VERSION 5.7 ;
  NOWIREEXTENSIONATPIN ON ;
  DIVIDERCHAR "/" ;
  BUSBITCHARS "[]" ;
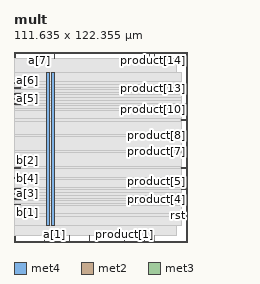
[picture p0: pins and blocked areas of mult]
MACRO mult
  CLASS BLOCK ;
  FOREIGN mult ;
  ORIGIN 0.000 0.000 ;
  SIZE 111.635 BY 122.355 ;
  PIN VGND
    DIRECTION INOUT ;
    USE GROUND ;
    PORT
      LAYER met4 ;
        RECT 24.340 10.640 25.940 109.040 ;
    END
  END VGND
  PIN VPWR
    DIRECTION INOUT ;
    USE POWER ;
    PORT
      LAYER met4 ;
        RECT 21.040 10.640 22.640 109.040 ;
    END
  END VPWR
  PIN a[0]
    DIRECTION INPUT ;
    USE SIGNAL ;
    ANTENNAGATEAREA 0.196500 ;
    PORT
      LAYER met2 ;
        RECT 35.510 0.000 35.790 4.000 ;
    END
  END a[0]
  PIN a[1]
    DIRECTION INPUT ;
    USE SIGNAL ;
    ANTENNAGATEAREA 0.196500 ;
    PORT
      LAYER met2 ;
        RECT 25.850 0.000 26.130 4.000 ;
    END
  END a[1]
  PIN a[2]
    DIRECTION INPUT ;
    USE SIGNAL ;
    ANTENNAGATEAREA 0.196500 ;
    PORT
      LAYER met3 ;
        RECT 0.000 27.240 4.000 27.840 ;
    END
  END a[2]
  PIN a[3]
    DIRECTION INPUT ;
    USE SIGNAL ;
    ANTENNAGATEAREA 0.196500 ;
    PORT
      LAYER met3 ;
        RECT 0.000 30.640 4.000 31.240 ;
    END
  END a[3]
  PIN a[4]
    DIRECTION INPUT ;
    USE SIGNAL ;
    ANTENNAGATEAREA 0.196500 ;
    PORT
      LAYER met3 ;
        RECT 0.000 88.440 4.000 89.040 ;
    END
  END a[4]
  PIN a[5]
    DIRECTION INPUT ;
    USE SIGNAL ;
    ANTENNAGATEAREA 0.196500 ;
    PORT
      LAYER met3 ;
        RECT 0.000 91.840 4.000 92.440 ;
    END
  END a[5]
  PIN a[6]
    DIRECTION INPUT ;
    USE SIGNAL ;
    ANTENNAGATEAREA 0.196500 ;
    PORT
      LAYER met3 ;
        RECT 0.000 98.640 4.000 99.240 ;
    END
  END a[6]
  PIN a[7]
    DIRECTION INPUT ;
    USE SIGNAL ;
    ANTENNAGATEAREA 0.196500 ;
    PORT
      LAYER met2 ;
        RECT 16.190 118.355 16.470 122.355 ;
    END
  END a[7]
  PIN b[0]
    DIRECTION INPUT ;
    USE SIGNAL ;
    ANTENNAGATEAREA 0.196500 ;
    PORT
      LAYER met2 ;
        RECT 19.410 0.000 19.690 4.000 ;
    END
  END b[0]
  PIN b[1]
    DIRECTION INPUT ;
    USE SIGNAL ;
    ANTENNAGATEAREA 0.196500 ;
    PORT
      LAYER met3 ;
        RECT 0.000 23.840 4.000 24.440 ;
    END
  END b[1]
  PIN b[2]
    DIRECTION INPUT ;
    USE SIGNAL ;
    ANTENNAGATEAREA 0.196500 ;
    PORT
      LAYER met3 ;
        RECT 0.000 47.640 4.000 48.240 ;
    END
  END b[2]
  PIN b[3]
    DIRECTION INPUT ;
    USE SIGNAL ;
    ANTENNAGATEAREA 0.196500 ;
    PORT
      LAYER met3 ;
        RECT 0.000 34.040 4.000 34.640 ;
    END
  END b[3]
  PIN b[4]
    DIRECTION INPUT ;
    USE SIGNAL ;
    ANTENNAGATEAREA 0.196500 ;
    PORT
      LAYER met3 ;
        RECT 0.000 40.840 4.000 41.440 ;
    END
  END b[4]
  PIN b[5]
    DIRECTION INPUT ;
    USE SIGNAL ;
    ANTENNAGATEAREA 0.196500 ;
    PORT
      LAYER met3 ;
        RECT 0.000 95.240 4.000 95.840 ;
    END
  END b[5]
  PIN b[6]
    DIRECTION INPUT ;
    USE SIGNAL ;
    ANTENNAGATEAREA 0.196500 ;
    PORT
      LAYER met2 ;
        RECT 22.630 118.355 22.910 122.355 ;
    END
  END b[6]
  PIN b[7]
    DIRECTION INPUT ;
    USE SIGNAL ;
    ANTENNAGATEAREA 0.196500 ;
    PORT
      LAYER met2 ;
        RECT 25.850 118.355 26.130 122.355 ;
    END
  END b[7]
  PIN clk
    DIRECTION INPUT ;
    USE SIGNAL ;
    ANTENNAGATEAREA 0.852000 ;
    PORT
      LAYER met3 ;
        RECT 0.000 102.040 4.000 102.640 ;
    END
  END clk
  PIN product[0]
    DIRECTION OUTPUT ;
    USE SIGNAL ;
    ANTENNADIFFAREA 0.445500 ;
    PORT
      LAYER met2 ;
        RECT 48.390 0.000 48.670 4.000 ;
    END
  END product[0]
  PIN product[10]
    DIRECTION OUTPUT ;
    USE SIGNAL ;
    ANTENNADIFFAREA 0.445500 ;
    PORT
      LAYER met3 ;
        RECT 107.635 85.040 111.635 85.640 ;
    END
  END product[10]
  PIN product[11]
    DIRECTION OUTPUT ;
    USE SIGNAL ;
    ANTENNADIFFAREA 0.445500 ;
    PORT
      LAYER met3 ;
        RECT 107.635 88.440 111.635 89.040 ;
    END
  END product[11]
  PIN product[12]
    DIRECTION OUTPUT ;
    USE SIGNAL ;
    ANTENNADIFFAREA 0.445500 ;
    PORT
      LAYER met3 ;
        RECT 107.635 95.240 111.635 95.840 ;
    END
  END product[12]
  PIN product[13]
    DIRECTION OUTPUT ;
    USE SIGNAL ;
    ANTENNADIFFAREA 0.445500 ;
    PORT
      LAYER met3 ;
        RECT 107.635 98.640 111.635 99.240 ;
    END
  END product[13]
  PIN product[14]
    DIRECTION OUTPUT ;
    USE SIGNAL ;
    ANTENNADIFFAREA 0.445500 ;
    PORT
      LAYER met2 ;
        RECT 90.250 118.355 90.530 122.355 ;
    END
  END product[14]
  PIN product[15]
    DIRECTION OUTPUT ;
    USE SIGNAL ;
    ANTENNADIFFAREA 0.445500 ;
    PORT
      LAYER met2 ;
        RECT 87.030 118.355 87.310 122.355 ;
    END
  END product[15]
  PIN product[1]
    DIRECTION OUTPUT ;
    USE SIGNAL ;
    ANTENNADIFFAREA 0.445500 ;
    PORT
      LAYER met2 ;
        RECT 70.930 0.000 71.210 4.000 ;
    END
  END product[1]
  PIN product[2]
    DIRECTION OUTPUT ;
    USE SIGNAL ;
    ANTENNADIFFAREA 0.445500 ;
    PORT
      LAYER met2 ;
        RECT 83.810 0.000 84.090 4.000 ;
    END
  END product[2]
  PIN product[3]
    DIRECTION OUTPUT ;
    USE SIGNAL ;
    ANTENNADIFFAREA 0.445500 ;
    PORT
      LAYER met2 ;
        RECT 90.250 0.000 90.530 4.000 ;
    END
  END product[3]
  PIN product[4]
    DIRECTION OUTPUT ;
    USE SIGNAL ;
    ANTENNADIFFAREA 0.445500 ;
    PORT
      LAYER met3 ;
        RECT 107.635 27.240 111.635 27.840 ;
    END
  END product[4]
  PIN product[5]
    DIRECTION OUTPUT ;
    USE SIGNAL ;
    ANTENNADIFFAREA 0.445500 ;
    PORT
      LAYER met3 ;
        RECT 107.635 34.040 111.635 34.640 ;
    END
  END product[5]
  PIN product[6]
    DIRECTION OUTPUT ;
    USE SIGNAL ;
    ANTENNADIFFAREA 0.445500 ;
    PORT
      LAYER met3 ;
        RECT 107.635 47.640 111.635 48.240 ;
    END
  END product[6]
  PIN product[7]
    DIRECTION OUTPUT ;
    USE SIGNAL ;
    ANTENNADIFFAREA 0.445500 ;
    PORT
      LAYER met3 ;
        RECT 107.635 57.840 111.635 58.440 ;
    END
  END product[7]
  PIN product[8]
    DIRECTION OUTPUT ;
    USE SIGNAL ;
    ANTENNADIFFAREA 0.445500 ;
    PORT
      LAYER met3 ;
        RECT 107.635 68.040 111.635 68.640 ;
    END
  END product[8]
  PIN product[9]
    DIRECTION OUTPUT ;
    USE SIGNAL ;
    ANTENNADIFFAREA 0.445500 ;
    PORT
      LAYER met3 ;
        RECT 107.635 78.240 111.635 78.840 ;
    END
  END product[9]
  PIN rst
    DIRECTION INPUT ;
    USE SIGNAL ;
    ANTENNAGATEAREA 0.196500 ;
    PORT
      LAYER met3 ;
        RECT 107.635 17.040 111.635 17.640 ;
    END
  END rst
  OBS
      LAYER nwell ;
        RECT 5.330 10.795 105.990 108.885 ;
      LAYER li1 ;
        RECT 5.520 10.795 105.800 108.885 ;
      LAYER met1 ;
        RECT 0.530 10.640 106.100 109.040 ;
      LAYER met2 ;
        RECT 0.550 118.075 15.910 118.355 ;
        RECT 16.750 118.075 22.350 118.355 ;
        RECT 23.190 118.075 25.570 118.355 ;
        RECT 26.410 118.075 86.750 118.355 ;
        RECT 87.590 118.075 89.970 118.355 ;
        RECT 90.810 118.075 104.330 118.355 ;
        RECT 0.550 4.280 104.330 118.075 ;
        RECT 0.550 4.000 19.130 4.280 ;
        RECT 19.970 4.000 25.570 4.280 ;
        RECT 26.410 4.000 35.230 4.280 ;
        RECT 36.070 4.000 48.110 4.280 ;
        RECT 48.950 4.000 70.650 4.280 ;
        RECT 71.490 4.000 83.530 4.280 ;
        RECT 84.370 4.000 89.970 4.280 ;
        RECT 90.810 4.000 104.330 4.280 ;
      LAYER met3 ;
        RECT 0.525 103.040 107.635 108.965 ;
        RECT 4.400 101.640 107.635 103.040 ;
        RECT 0.525 99.640 107.635 101.640 ;
        RECT 4.400 98.240 107.235 99.640 ;
        RECT 0.525 96.240 107.635 98.240 ;
        RECT 4.400 94.840 107.235 96.240 ;
        RECT 0.525 92.840 107.635 94.840 ;
        RECT 4.400 91.440 107.635 92.840 ;
        RECT 0.525 89.440 107.635 91.440 ;
        RECT 4.400 88.040 107.235 89.440 ;
        RECT 0.525 86.040 107.635 88.040 ;
        RECT 0.525 84.640 107.235 86.040 ;
        RECT 0.525 79.240 107.635 84.640 ;
        RECT 0.525 77.840 107.235 79.240 ;
        RECT 0.525 69.040 107.635 77.840 ;
        RECT 0.525 67.640 107.235 69.040 ;
        RECT 0.525 58.840 107.635 67.640 ;
        RECT 0.525 57.440 107.235 58.840 ;
        RECT 0.525 48.640 107.635 57.440 ;
        RECT 4.400 47.240 107.235 48.640 ;
        RECT 0.525 41.840 107.635 47.240 ;
        RECT 4.400 40.440 107.635 41.840 ;
        RECT 0.525 35.040 107.635 40.440 ;
        RECT 4.400 33.640 107.235 35.040 ;
        RECT 0.525 31.640 107.635 33.640 ;
        RECT 4.400 30.240 107.635 31.640 ;
        RECT 0.525 28.240 107.635 30.240 ;
        RECT 4.400 26.840 107.235 28.240 ;
        RECT 0.525 24.840 107.635 26.840 ;
        RECT 4.400 23.440 107.635 24.840 ;
        RECT 0.525 18.040 107.635 23.440 ;
        RECT 0.525 16.640 107.235 18.040 ;
        RECT 0.525 10.715 107.635 16.640 ;
      LAYER met4 ;
        RECT 3.975 100.135 4.305 102.505 ;
  END
END mult
END LIBRARY

